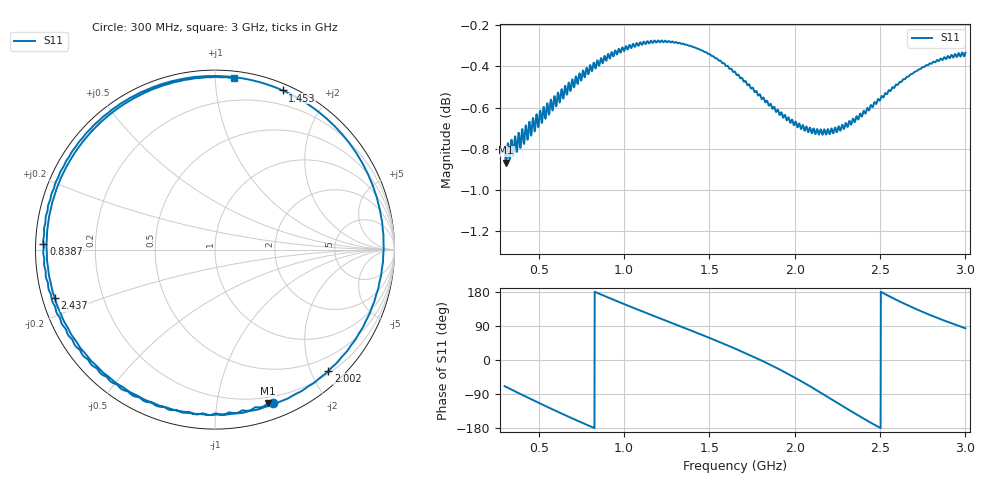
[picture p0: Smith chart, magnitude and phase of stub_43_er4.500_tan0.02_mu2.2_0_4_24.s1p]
! Chirptenna · simulación 3D de un stub abierto
# HZ S RI R 50
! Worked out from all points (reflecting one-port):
!   2001 points, 300 MHz to 3 GHz, reference 50 ohm
!   lowest |S11| = -0.9 dB at 308.1 MHz (marker M1), VSWR 20.03, Z = 7.4 - j69.8 ohm
!   phase of S11 starts at -69 deg and turns -567 deg over the sweep
!   S11 on the Smith chart (normalised r, x): 300 MHz: 0.14, -1.44; 838.6 MHz: 0.02, +0.02; 1.453 GHz: 0.06, +1.51; 2.002 GHz: 0.24, -2.28; 2.437 GHz: 0.04, -0.15; 3 GHz: 0.04, +1.12
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3e8  0.3258 -0.8526
3.081e8  0.297 -0.8548
3.9315e8  0.00444 -0.9125
4.7415e8  -0.2794 -0.8783
5.5785e8  -0.5408 -0.7571
6.375e8  -0.7437 -0.5776
7.3065e8  -0.8939 -0.3113
8.3865e8  -0.9559 0.0327
9.75e8  -0.8518 0.4497
1.14915e9  -0.4949 0.8314
1.3125e9  -0.0317 0.967
1.4529e9  0.3775 0.8867
1.5501e9  0.6268 0.7254
1.65e9  0.8227 0.4794
1.74315e9  0.9239 0.1904
1.82685e9  0.9309 -0.0985
1.9092e9  0.8455 -0.3868
1.9875e9  0.6737 -0.636
2.00235e9  0.6322 -0.6761
2.08335e9  0.35 -0.8523
2.16435e9  0.00907 -0.9193
2.244e9  -0.3362 -0.8573
2.325e9  -0.6389 -0.6696
2.43705e9  -0.8924 -0.2688
2.541e9  -0.9292 0.144
2.6625e9  -0.7706 0.5548
2.8245e9  -0.3741 0.8812
3e9  0.1063 0.9565
